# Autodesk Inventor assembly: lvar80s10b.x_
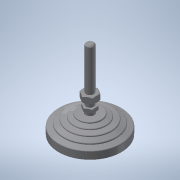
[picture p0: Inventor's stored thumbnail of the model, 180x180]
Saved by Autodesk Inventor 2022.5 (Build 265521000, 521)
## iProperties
Part Number: lvar80s10b.x_
Material: 一般
Document SubType Name: Assembly
Designer: ImaoCorp
Sending System: SOLIDWORKS 2017-2017317
MC: AMD64
MC_MODEL: Intel64 Family 6 Model 60 Stepping 3, GenuineIntel
OS: Windows_NT
FRU: Parasolid Version 29.0, build 201,  4-17-2017
FORMAT: text
GUISE: transmit
KEY: lvar80s10b
FILE: lvar80s10b.x_t
DATE: Mon Jul 01 18:15:33 2019
Author: ImaoCorp
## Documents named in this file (3)
- X:\14_SW2022-Inv2022\00_全2023-1023新製品(TCC)まで\l\lvar80s10b\LVAR80S10B.iam
- X:\14_SW2022-Inv2022\00_全2023-1023新製品(TCC)まで\l\lvar80s10b\lvar80s10b_01.ipt
- X:\14_SW2022-Inv2022\00_全2023-1023新製品(TCC)まで\l\lvar80s10b\lvar80s10b_02.ipt
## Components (2 placed, 2 different names)
1. lvar80s10b_01
2. lvar80s10b_02
